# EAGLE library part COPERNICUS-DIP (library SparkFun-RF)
Copernicus II dip module, SKU GPS-10923

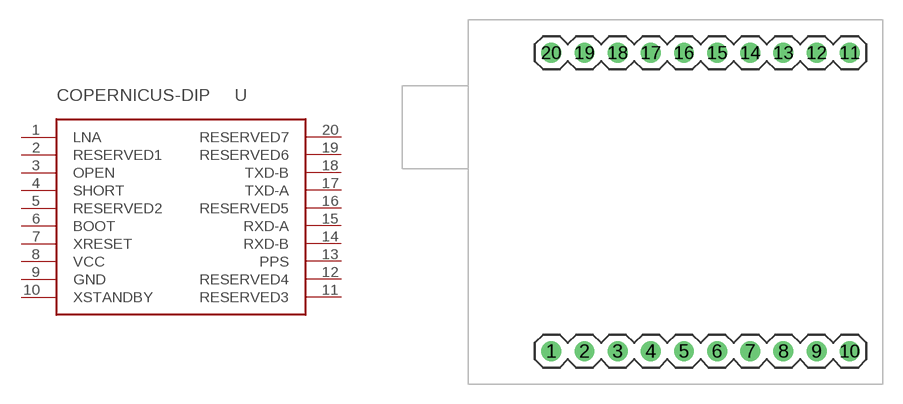
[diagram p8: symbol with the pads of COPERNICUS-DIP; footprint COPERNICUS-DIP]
Designator prefix -

## COPERNICUS-DIPPTH  [COPERNICUS-DIP]
1  LNA
2  RESERVED1
3  OPEN
4  SHORT
5  RESERVED2
6  BOOT
7  XRESET
8  VCC
9  GND
10  XSTANDBY
11  RESERVED3
12  RESERVED4
13  PPS
14  RXD-B
15  RXD-A
16  RESERVED5
17  TXD-A
18  TXD-B
19  RESERVED6
20  RESERVED7

## Footprint COPERNICUS-DIP (pad centres in mm)
drill 1.016: 1 0,0; 2 2.54,0; 3 5.08,0; 4 7.62,0; 5 10.16,0; 6 12.7,0; 7 15.24,0; 8 17.78,0; 9 20.32,0; 10 22.86,0; 11 22.86,22.86; 12 20.32,22.86; 13 17.78,22.86; 14 15.24,22.86; 15 12.7,22.86; 16 10.16,22.86; 17 7.62,22.86; 18 5.08,22.86; 19 2.54,22.86; 20 0,22.86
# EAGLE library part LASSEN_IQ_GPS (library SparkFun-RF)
Lassen iq 12-Channel GPS receiver. Schematic and footprint production proven. Spark Fun Electronics SKU : GPS-00163. Surface mount mating connector : GPS-00170

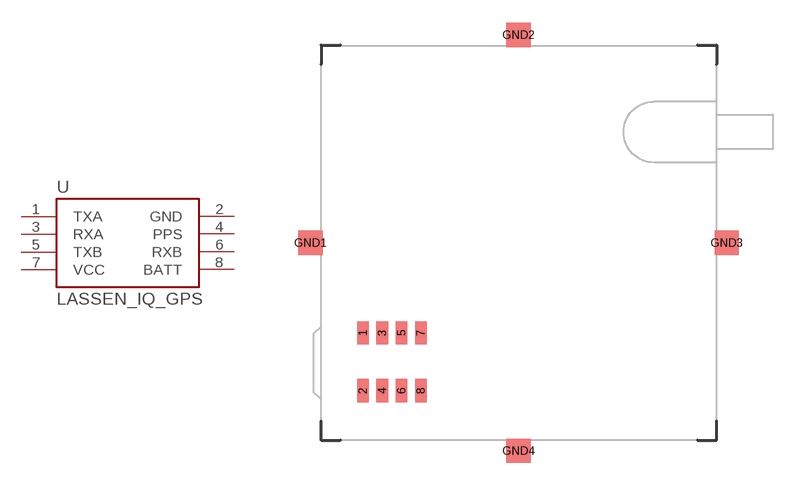
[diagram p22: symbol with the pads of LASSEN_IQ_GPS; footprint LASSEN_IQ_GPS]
Designator prefix -

## LASSEN_IQ_GPSLASSEN  [LASSEN_IQ_GPS]
1  TXA  out
2  GND  pwr
3  RXA  in
4  PPS  out
5  TXB  out
6  RXB  in
7  VCC  pwr
8  BATT  pwr

## Footprint LASSEN_IQ_GPS (pad centres in mm)
smd 0.762 x 1.524: 1 2.752,7.076; 2 2.752,3.266; 3 4.022,7.076; 4 4.022,3.266; 5 5.292,7.076; 6 5.292,3.266; 7 6.562,7.076; 8 6.562,3.266
smd 1.6 x 1.6: GND1 -0.7,13; GND2 13,26.7; GND3 26.7,13; GND4 13,-0.7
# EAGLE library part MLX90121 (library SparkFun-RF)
MLX90121 13.56MHz RFID Transceiver

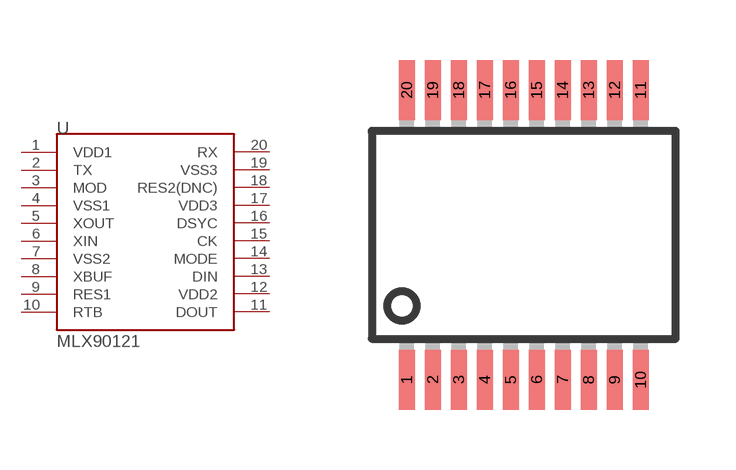
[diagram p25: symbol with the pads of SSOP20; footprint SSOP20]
Designator prefix U

## MLX90121_  [SSOP20]
1  VDD1
2  TX
3  MOD
4  VSS1
5  XOUT
6  XIN
7  VSS2
8  XBUF
9  RES1
10  RTB
11  DOUT
12  VDD2
13  DIN
14  MODE
15  CK
16  DSYC
17  VDD3
18  RES2(DNC)
19  VSS3
20  RX

## Footprint SSOP20 (pad centres in mm)
Shrink Small Outline Package package type SS
smd 0.4 x 1.5: 1 -2.925,-3.625; 2 -2.275,-3.625; 3 -1.625,-3.625; 4 -0.975,-3.625; 5 -0.325,-3.625; 6 0.325,-3.625; 7 0.975,-3.625; 8 1.625,-3.625; 9 2.275,-3.625; 10 2.925,-3.625; 11 2.925,3.625; 12 2.275,3.625; 13 1.625,3.625; 14 0.975,3.625; 15 0.325,3.625; 16 -0.325,3.625; 17 -0.975,3.625; 18 -1.625,3.625; 19 -2.275,3.625; 20 -2.925,3.625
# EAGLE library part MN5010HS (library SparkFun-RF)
MN5010HS GPS Receiver Module. Packagse GR-10 and MN5010HS are NOT tested with this device.

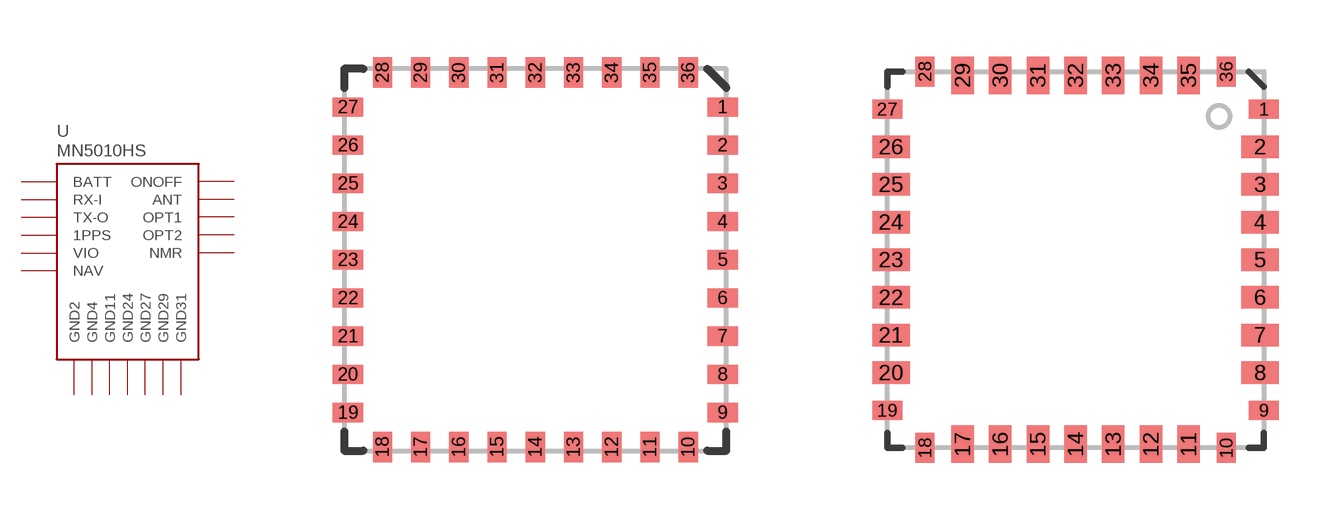
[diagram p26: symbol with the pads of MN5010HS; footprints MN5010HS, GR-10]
Designator prefix -

## MN5010HSSMD  [MN5010HS]

## MN5010HS  [GR-10]
2  GND2
4  GND4
7  RX-I
8  TX-O
9  1PPS
11  GND11
12  VIO
13  OPT1
14  OPT2
20  NAV
22  ONOFF
23  NMR
24  GND24
27  GND27
29  GND29
30  ANT
31  GND31
33  BATT

## Footprint MN5010HS (pad centres in mm)
MN5010HS GPS Module
smd 0.8 x 0.5: 1 4.9,4; 2 4.9,3; 3 4.9,2; 4 4.9,1; 5 4.9,0; 6 4.9,-1; 7 4.9,-2; 8 4.9,-3; 9 4.9,-4; 19 -4.9,-4; 20 -4.9,-3; 21 -4.9,-2; 22 -4.9,-1; 23 -4.9,0; 24 -4.9,1; 25 -4.9,2; 26 -4.9,3; 27 -4.9,4
smd 0.5 x 0.8: 10 4,-4.9; 11 3,-4.9; 12 2,-4.9; 13 1,-4.9; 14 0,-4.9; 15 -1,-4.9; 16 -2,-4.9; 17 -3,-4.9; 18 -4,-4.9; 28 -4,4.9; 29 -3,4.9; 30 -2,4.9; 31 -1,4.9; 32 0,4.9; 33 1,4.9; 34 2,4.9; 35 3,4.9; 36 4,4.9

## Footprint GR-10 (pad centres in mm)
smd 0.8 x 0.5: 1 5,4; 9 5,-4; 19 -5,-4; 27 -5,4
smd 1 x 0.6: 2 4.9,3; 3 4.9,2; 4 4.9,1; 5 4.9,0; 6 4.9,-1; 7 4.9,-2; 8 4.9,-3; 20 -4.9,-3; 21 -4.9,-2; 22 -4.9,-1; 23 -4.9,0; 24 -4.9,1; 25 -4.9,2; 26 -4.9,3
smd 0.5 x 0.8: 10 4,-5; 18 -4,-5; 28 -4,5; 36 4,5
smd 0.6 x 1: 11 3,-4.9; 12 2,-4.9; 13 1,-4.9; 14 0,-4.9; 15 -1,-4.9; 16 -2,-4.9; 17 -3,-4.9; 29 -3,4.9; 30 -2,4.9; 31 -1,4.9; 32 0,4.9; 33 1,4.9; 34 2,4.9; 35 3,4.9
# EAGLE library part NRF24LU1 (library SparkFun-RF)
2.4GHz transceiver

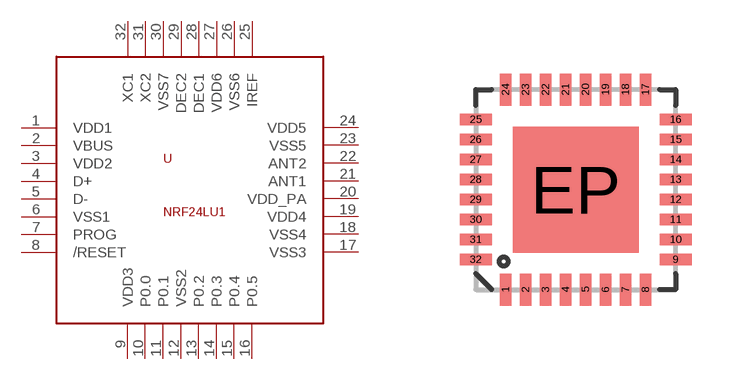
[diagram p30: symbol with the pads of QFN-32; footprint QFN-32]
Designator prefix -

## NRF24LU1  [QFN-32]
1  VDD1
2  VBUS
3  VDD2
4  D+
5  D-
6  VSS1
7  PROG
8  /RESET
9  VDD3
10  P0.0
11  P0.1
12  VSS2
13  P0.2
14  P0.3
15  P0.4
16  P0.5
17  VSS3
18  VSS4
19  VDD4
20  VDD_PA
21  ANT1
22  ANT2
23  VSS5
24  VDD5
25  IREF
26  VSS6
27  VDD6
28  DEC1
29  DEC2
30  VSS7
31  XC2
32  XC1

## Footprint QFN-32 (pad centres in mm)
QFN 32-Pin package w/ Thermal Pad ***Unproven*** Applicable Parts: TLC5940
smd 0.285 x 0.8: 1 -1.75,-2.5; 2 -1.25,-2.5; 3 -0.75,-2.5; 4 -0.25,-2.5; 5 0.25,-2.5; 6 0.75,-2.5; 7 1.25,-2.5; 8 1.75,-2.5; 17 1.75,2.5; 18 1.25,2.5; 19 0.75,2.5; 20 0.25,2.5; 21 -0.25,2.5; 22 -0.75,2.5; 23 -1.25,2.5; 24 -1.75,2.5
smd 0.8 x 0.285: 9 2.5,-1.75; 10 2.5,-1.25; 11 2.5,-0.75; 12 2.5,-0.25; 13 2.5,0.25; 14 2.5,0.75; 15 2.5,1.25; 16 2.5,1.75; 25 -2.5,1.75; 26 -2.5,1.25; 27 -2.5,0.75; 28 -2.5,0.25; 29 -2.5,-0.25; 30 -2.5,-0.75; 31 -2.5,-1.25; 32 -2.5,-1.75
smd 3.15 x 3.15: EP 0,0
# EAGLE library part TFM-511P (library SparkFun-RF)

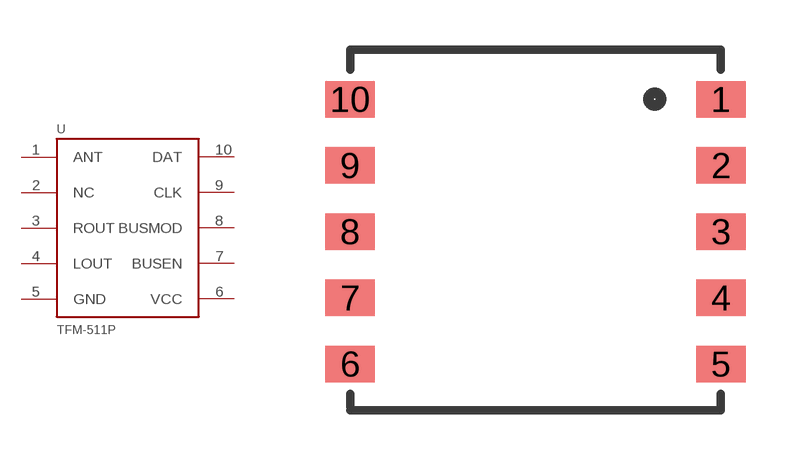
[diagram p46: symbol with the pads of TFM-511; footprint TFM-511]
Designator prefix -

## TFM-511P  [TFM-511]
1  ANT
2  NC
3  ROUT
4  LOUT
5  GND
6  VCC
7  BUSEN
8  BUSMOD
9  CLK
10  DAT

## Footprint TFM-511 (pad centres in mm)
smd 1.5 x 1.1: 1 5.6,4; 2 5.6,2; 3 5.6,0; 4 5.6,-2; 5 5.6,-4; 6 -5.6,-4; 7 -5.6,-2; 8 -5.6,0; 9 -5.6,2; 10 -5.6,4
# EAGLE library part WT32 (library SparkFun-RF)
Blue Giga Audio Bluetooth Module Footprint is not confirmed yet.

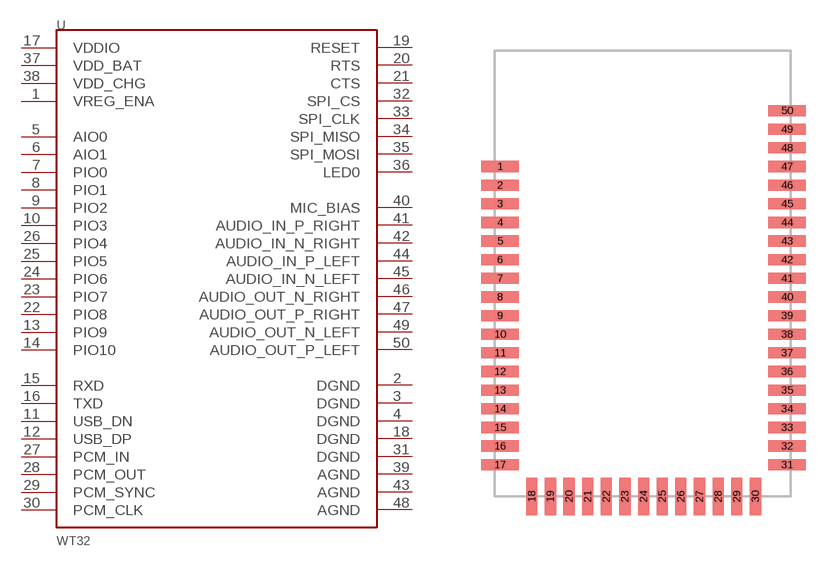
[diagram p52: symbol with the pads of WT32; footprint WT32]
Designator prefix -

## WT32  [WT32]
1  VREG_ENA
2  DGND
3  DGND
4  DGND
5  AIO0
6  AIO1
7  PIO0
8  PIO1
9  PIO2
10  PIO3
11  USB_DN
12  USB_DP
13  PIO9
14  PIO10
15  RXD
16  TXD
17  VDDIO
18  DGND
19  RESET
20  RTS
21  CTS
22  PIO8
23  PIO7
24  PIO6
25  PIO5
26  PIO4
27  PCM_IN
28  PCM_OUT
29  PCM_SYNC
30  PCM_CLK
31  DGND
32  SPI_CS
33  SPI_CLK
34  SPI_MISO
35  SPI_MOSI
36  LED0
37  VDD_BAT
38  VDD_CHG
39  AGND
40  MIC_BIAS
41  AUDIO_IN_P_RIGHT
42  AUDIO_IN_N_RIGHT
43  AGND
44  AUDIO_IN_P_LEFT
45  AUDIO_IN_N_LEFT
46  AUDIO_OUT_N_RIGHT
47  AUDIO_OUT_P_RIGHT
48  AGND
49  AUDIO_OUT_N_LEFT
50  AUDIO_OUT_P_LEFT

## Footprint WT32 (pad centres in mm)
smd 2 x 0.6: 1 -7.7,5.7; 2 -7.7,4.7; 3 -7.7,3.7; 4 -7.7,2.7; 5 -7.7,1.7; 6 -7.7,0.7; 7 -7.7,-0.3; 8 -7.7,-1.3; 9 -7.7,-2.3; 10 -7.7,-3.3; 11 -7.7,-4.3; 12 -7.7,-5.3; 13 -7.7,-6.3; 14 -7.7,-7.3; 15 -7.7,-8.3; 16 -7.7,-9.3; 17 -7.7,-10.3; 31 7.7,-10.3; 32 7.7,-9.3; 33 7.7,-8.3; 34 7.7,-7.3; 35 7.7,-6.3; 36 7.7,-5.3; 37 7.7,-4.3; 38 7.7,-3.3; 39 7.7,-2.3; 40 7.7,-1.3; 41 7.7,-0.3; 42 7.7,0.7; 43 7.7,1.7; 44 7.7,2.7; 45 7.7,3.7; 46 7.7,4.7; 47 7.7,5.7; 48 7.7,6.7; 49 7.7,7.7; 50 7.7,8.7
smd 0.6 x 2: 18 -6,-12; 19 -5,-12; 20 -4,-12; 21 -3,-12; 22 -2,-12; 23 -1,-12; 24 0,-12; 25 1,-12; 26 2,-12; 27 3,-12; 28 4,-12; 29 5,-12; 30 6,-12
